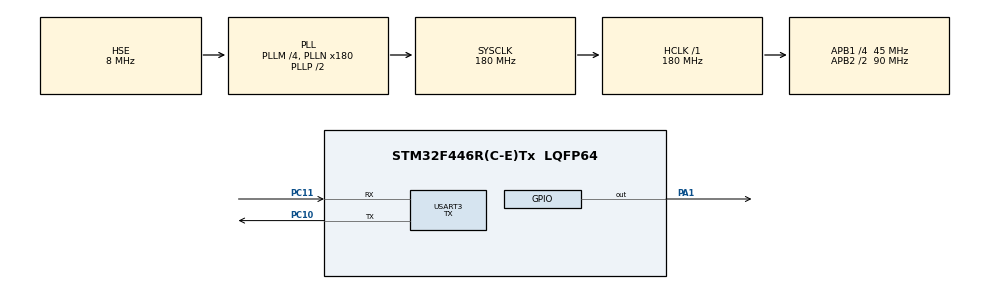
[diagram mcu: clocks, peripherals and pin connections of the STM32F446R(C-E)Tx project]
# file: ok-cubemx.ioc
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FREERTOS.Tasks01=defaultTask,24,128,StartDefaultTask,Default,NULL,Dynamic,NULL,NULL
Mcu.Family=STM32F4
Mcu.Name=STM32F446R(C-E)Tx
Mcu.Package=LQFP64
NVIC.PriorityGroup=NVIC_PRIORITYGROUP_4
NVIC.TIM5_IRQn=true\:0\:0\:false\:false\:true\:false\:false\:true
NVIC.TimeBase=TIM5_IRQn
NVIC.TimeBaseIP=TIM5
PA1.Signal=GPIO_Output
PC10.Mode=Asynchronous
PC10.Signal=USART3_TX
PC11.Mode=Asynchronous
PC11.Signal=USART3_RX
PH0-OSC_IN.Mode=HSE-External-Oscillator
PH0-OSC_IN.Signal=RCC_OSC_IN
PH1-OSC_OUT.Mode=HSE-External-Oscillator
PH1-OSC_OUT.Signal=RCC_OSC_OUT
ProjectManager.HeapSize=0x200
ProjectManager.StackSize=0x400
ProjectManager.TargetToolchain=Makefile
RCC.AHBFreq_Value=180000000
RCC.APB1CLKDivider=RCC_HCLK_DIV4
RCC.APB1Freq_Value=45000000
RCC.APB1TimFreq_Value=90000000
RCC.APB2CLKDivider=RCC_HCLK_DIV2
RCC.APB2Freq_Value=90000000
RCC.APB2TimFreq_Value=180000000
RCC.CortexFreq_Value=180000000
RCC.HCLKFreq_Value=180000000
RCC.HSE_VALUE=8000000
RCC.PLLM=4
RCC.PLLN=180
RCC.PLLSourceVirtual=RCC_PLLSOURCE_HSE
RCC.SYSCLKFreq_VALUE=180000000
RCC.SYSCLKSource=RCC_SYSCLKSOURCE_PLLCLK
RCC.USBFreq_Value=180000000
RCC.VCOOutputFreq_Value=360000000
USART3.Mode=MODE_TX
USART3.VirtualMode=VM_ASYNC
VP_FREERTOS_VS_CMSIS_V2.Mode=CMSIS_V2
VP_SYS_VS_tim5.Mode=TIM5
board=custom

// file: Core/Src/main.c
/* USER CODE BEGIN Header */
/**
  ******************************************************************************
  * @file           : main.c
  * @brief          : Main program body
  ******************************************************************************
  * @attention
  *
  * <h2><center>&copy; Copyright (c) 2021 STMicroelectronics.
  * All rights reserved.</center></h2>
  *
  * This software component is licensed by ST under BSD 3-Clause license,
  * the "License"; You may not use this file except in compliance with the
  * License. You may obtain a copy of the License at:
  *                        opensource.org/licenses/BSD-3-Clause
  *
  ******************************************************************************
  */
/* USER CODE END Header */
#include "main.h"
#include "cmsis_os.h"

/* USER CODE BEGIN Includes */
#include <string.h>
/* USER CODE END Includes */

/* USER CODE BEGIN PD */
#define BLUE_LED_PIN GPIO_PIN_7
#define BLUE_LED_PORT GPIOB

#define RED_LED_PIN GPIO_PIN_13
#define RED_LED_PORT GPIOC

#define SUDO_DELAY_TIME 5000000
/* USER CODE END PD */

UART_HandleTypeDef huart3;

void SystemClock_Config(void);
static void MX_GPIO_Init(void);
static void MX_USART3_UART_Init(void);

/* USER CODE BEGIN PFP */

typedef uint32_t Counter;
Counter task1Counter, task2Counter;  // it is wise to add a simple counter to each task to ensure its executing
int priority = 1;
TaskHandle_t task1_handle, task2_handle; //
/* USER CODE END PFP */

/* USER CODE BEGIN 0 */
void incrementPriority()
{
  if (priority < 15) {
    priority++;
  } else {
    priority = 1;
  }
}

void vTask1(void *pvParameters)
{
  char msg[] = "Task 1 \n";
  while (1)
  {
    task1Counter++;
    HAL_UART_Transmit(&huart3, (uint8_t *)msg, strlen(msg), HAL_MAX_DELAY);
    HAL_GPIO_TogglePin(GPIOB, (uint16_t)pvParameters);
    for (int i = 0; i < SUDO_DELAY_TIME; i++){} // sudo delay
    incrementPriority();
    vTaskPrioritySet(task2_handle, priority);
  }
}

void vTask2(void *pvParameters)
{
  char msg[] = "Task 2 \n";
  while (1)
  {
    task2Counter++;
    HAL_UART_Transmit(&huart3, (uint8_t *)msg, strlen(msg), HAL_MAX_DELAY);
    HAL_GPIO_TogglePin(GPIOC, (uint16_t)pvParameters);
    for (int i = 0; i < SUDO_DELAY_TIME; i++){} // sudo delay
    incrementPriority();
    vTaskPrioritySet(task1_handle, priority);
  }
}
/* USER CODE END 0 */

int main(void)
{

  /* MCU Configuration--------------------------------------------------------*/

  /* Reset of all peripherals, Initializes the Flash interface and the Systick. */
  HAL_Init();

  /* Configure the system clock */
  SystemClock_Config();

  /* Initialize all configured peripherals */
  MX_GPIO_Init();
  MX_USART3_UART_Init();
  /* USER CODE BEGIN 2 */
  char serialData[4] = "a b ";

  xTaskCreate(vTask1, "Task 1", 100, (void *)BLUE_LED_PIN, 1, &task1_handle);
  xTaskCreate(vTask2, "Task 2", 100, (void *)RED_LED_PIN, 2, &task2_handle);

  vTaskStartScheduler();
  /* USER CODE END 2 */

  /* We should never get here as control is now taken by the scheduler */
  /* Infinite loop */
  while (1)
  {

  }
}

void SystemClock_Config(void)
{
  RCC_OscInitTypeDef RCC_OscInitStruct = {0};
  RCC_ClkInitTypeDef RCC_ClkInitStruct = {0};

  /** Configure the main internal regulator output voltage
  */
  __HAL_RCC_PWR_CLK_ENABLE();
  __HAL_PWR_VOLTAGESCALING_CONFIG(PWR_REGULATOR_VOLTAGE_SCALE1);
  /** Initializes the RCC Oscillators according to the specified parameters
  * in the RCC_OscInitTypeDef structure.
  */
  RCC_OscInitStruct.OscillatorType = RCC_OSCILLATORTYPE_HSE;
  RCC_OscInitStruct.HSEState = RCC_HSE_ON;
  RCC_OscInitStruct.PLL.PLLState = RCC_PLL_ON;
  RCC_OscInitStruct.PLL.PLLSource = RCC_PLLSOURCE_HSE;
  RCC_OscInitStruct.PLL.PLLM = 4;
  RCC_OscInitStruct.PLL.PLLN = 180;
  RCC_OscInitStruct.PLL.PLLP = RCC_PLLP_DIV2;
  RCC_OscInitStruct.PLL.PLLQ = 2;
  RCC_OscInitStruct.PLL.PLLR = 2;
  if (HAL_RCC_OscConfig(&RCC_OscInitStruct) != HAL_OK)
  {
    Error_Handler();
  }
  /** Activate the Over-Drive mode
  */
  if (HAL_PWREx_EnableOverDrive() != HAL_OK)
  {
    Error_Handler();
  }
  /** Initializes the CPU, AHB and APB buses clocks
  */
  RCC_ClkInitStruct.ClockType = RCC_CLOCKTYPE_HCLK|RCC_CLOCKTYPE_SYSCLK
                              |RCC_CLOCKTYPE_PCLK1|RCC_CLOCKTYPE_PCLK2;
  RCC_ClkInitStruct.SYSCLKSource = RCC_SYSCLKSOURCE_PLLCLK;
  RCC_ClkInitStruct.AHBCLKDivider = RCC_SYSCLK_DIV1;
  RCC_ClkInitStruct.APB1CLKDivider = RCC_HCLK_DIV4;
  RCC_ClkInitStruct.APB2CLKDivider = RCC_HCLK_DIV2;

  if (HAL_RCC_ClockConfig(&RCC_ClkInitStruct, FLASH_LATENCY_5) != HAL_OK)
  {
    Error_Handler();
  }
}

static void MX_USART3_UART_Init(void)
{

  huart3.Instance = USART3;
  huart3.Init.BaudRate = 115200;
  huart3.Init.WordLength = UART_WORDLENGTH_8B;
  huart3.Init.StopBits = UART_STOPBITS_1;
  huart3.Init.Parity = UART_PARITY_NONE;
  huart3.Init.Mode = UART_MODE_TX;
  huart3.Init.HwFlowCtl = UART_HWCONTROL_NONE;
  huart3.Init.OverSampling = UART_OVERSAMPLING_16;
  if (HAL_UART_Init(&huart3) != HAL_OK)
  {
    Error_Handler();
  }

}

static void MX_GPIO_Init(void)
{
  GPIO_InitTypeDef GPIO_InitStruct = {0};

  /* GPIO Ports Clock Enable */
  __HAL_RCC_GPIOH_CLK_ENABLE();
  __HAL_RCC_GPIOA_CLK_ENABLE();
  __HAL_RCC_GPIOB_CLK_ENABLE();
  __HAL_RCC_GPIOC_CLK_ENABLE();

  /*Configure GPIO pin Output Level */
  HAL_GPIO_WritePin(GPIOA, GPIO_PIN_1, GPIO_PIN_RESET);
  HAL_GPIO_WritePin(GPIOB, GPIO_PIN_7, GPIO_PIN_RESET);
  HAL_GPIO_WritePin(GPIOC, GPIO_PIN_13, GPIO_PIN_RESET);

  /*Configure GPIO pin : PA1 */
  GPIO_InitStruct.Pin = GPIO_PIN_1;
  GPIO_InitStruct.Mode = GPIO_MODE_OUTPUT_PP;
  GPIO_InitStruct.Pull = GPIO_NOPULL;
  GPIO_InitStruct.Speed = GPIO_SPEED_FREQ_LOW;
  HAL_GPIO_Init(GPIOA, &GPIO_InitStruct);

  GPIO_InitStruct.Pin = GPIO_PIN_7;
  GPIO_InitStruct.Mode = GPIO_MODE_OUTPUT_PP;
  GPIO_InitStruct.Pull = GPIO_NOPULL;
  GPIO_InitStruct.Speed = GPIO_SPEED_FREQ_LOW;
  HAL_GPIO_Init(GPIOB, &GPIO_InitStruct);

  GPIO_InitStruct.Pin = GPIO_PIN_13;
  GPIO_InitStruct.Mode = GPIO_MODE_OUTPUT_PP;
  GPIO_InitStruct.Pull = GPIO_NOPULL;
  GPIO_InitStruct.Speed = GPIO_SPEED_FREQ_LOW;
  HAL_GPIO_Init(GPIOC, &GPIO_InitStruct);
}

 /**
  * @brief  Period elapsed callback in non blocking mode
  * @note   This function is called  when TIM5 interrupt took place, inside
  * HAL_TIM_IRQHandler(). It makes a direct call to HAL_IncTick() to increment
  * a global variable "uwTick" used as application time base.
  * @param  htim : TIM handle
  * @retval None
  */
void HAL_TIM_PeriodElapsedCallback(TIM_HandleTypeDef *htim)
{
  if (htim->Instance == TIM5) {
    HAL_IncTick();
  }
}

void Error_Handler(void)
{
  __disable_irq();
  while (1)
  {
  }
}

/************************ (C) COPYRIGHT STMicroelectronics *****END OF FILE****/
